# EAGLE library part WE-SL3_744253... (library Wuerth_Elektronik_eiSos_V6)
SMD Common Mode Line Filter WE-SL3 - Small size - Low Profile, only 2.5 mm - High Impedance tp to 5000 ohm - High Current up to 700mA - Low leakage inductance - USB - CAN - Firewire - Data Lines - Power Lines

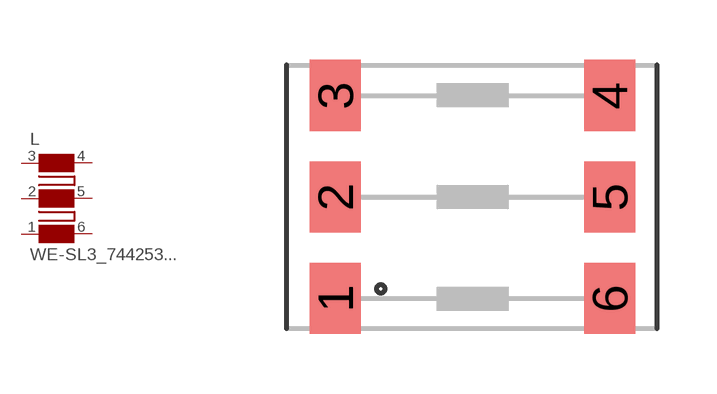
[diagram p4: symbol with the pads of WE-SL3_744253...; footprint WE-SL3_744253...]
Designator prefix L

## WE-SL3_744253...  [WE-SL3_744253...]
1  3  pas
2  2  pas
3  1  pas
4  6  pas
5  5  pas
6  4  pas

## Footprint WE-SL3_744253... (pad centres in mm)
SMD Common-Mode Line Filter WE-SL3
smd 1.27 x 1.78: 1 -3.44,-2.54; 2 -3.44,0; 3 -3.44,2.54; 4 3.42,2.54; 5 3.42,0; 6 3.42,-2.54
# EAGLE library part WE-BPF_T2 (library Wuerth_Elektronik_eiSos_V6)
SMD-Multilayer Chip Band-Pass Filter WE-BPF - low insertion loss - High attenuation - Guaranteed filter characteristics over a wide temperature range -- Rf applications in the frequency range up to 6GHz -- Wireless communcation systems like DECT, PACS, PHS, GSM,WLAN,Bluetooth,..

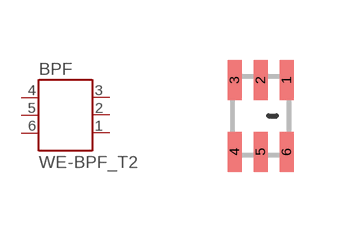
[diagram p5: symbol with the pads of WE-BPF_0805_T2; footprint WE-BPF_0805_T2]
Designator prefix BPF

## WE-BPF_T2_0805  [WE-BPF_0805_T2]
1  GND  pas
2  GND  pas
3  I/O  pas
4  GND  pas
5  GND  pas
6  I/O  pas

## Footprint WE-BPF_0805_T2 (pad centres in mm)
Multilayer Chip Band -Pass Filter WE-BPF
smd 0.35 x 1: 1 0.65,0.9; 2 0,0.9; 3 -0.65,0.9; 4 -0.65,-0.9; 5 0,-0.9; 6 0.65,-0.9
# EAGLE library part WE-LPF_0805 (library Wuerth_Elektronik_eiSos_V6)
Multilayer Chip Low-Pass Filters WE-LPF SMD 0603 - One inductor and three capacitors or two inductors and five capacitors in one component - Power capacity up to 3W - Low insertion loss and high attenuation in the stop-band -- RF-applications in the area of 0.8 to 6 GHz -- wireless communication systems like DECT,PACS,PHS,GSM, Bluetooth,...

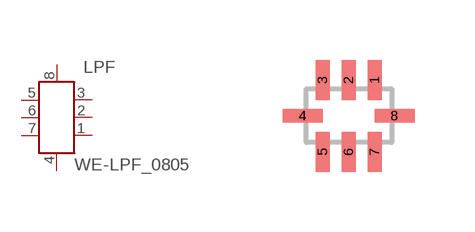
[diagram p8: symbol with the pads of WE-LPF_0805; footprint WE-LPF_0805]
Designator prefix LPF

## WE-LPF_0805  [WE-LPF_0805]
1  GND  pwr
2  NC  nc
3  GND  pwr
4  OUT  out
5  GND  pwr
6  NC  nc
7  GND  pwr
8  IN  in

## Footprint WE-LPF_0805 (pad centres in mm)
Multilayer Chip Low-Pass Filters WE-LPF
smd 0.35 x 1: 1 0.65,0.9; 2 0,0.9; 3 -0.65,0.9; 5 -0.65,-0.9; 6 0,-0.9; 7 0.65,-0.9
smd 1 x 0.35: 4 -1.15,0; 8 1.15,0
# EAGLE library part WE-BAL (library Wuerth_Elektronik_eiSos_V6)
Multilayer Chip Baluns WE-BAL - Low loss SMD Balun with balanced impedance of 50 to 200 Ohm - Operating temperature: -40°C to +85°C - Power Capacity: 3 W max. -- RF-applications in the area of 0.8 to 6 GHz -- Download S-Parameter on www.we-online.com -- Wireless communication systems like DECT, PACS, PHS, GSM, WLAN, Bluetooth

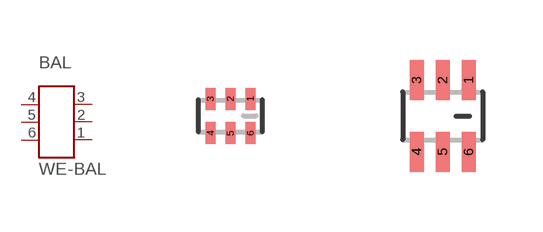
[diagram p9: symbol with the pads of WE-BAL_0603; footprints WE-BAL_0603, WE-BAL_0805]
Designator prefix BAL

## WE-BAL_0603  [WE-BAL_0603]
1  1  pas
2  2  pas
3  3  pas
4  4  pas
5  5  pas
6  6  pas

## WE-BAL_0805  [WE-BAL_0805]
Pads as for WE-BAL_0603

## WE-BAL_1206  [WE-BAL_1206]
Pads as for WE-BAL_0603

## Footprint WE-BAL_0603 (pad centres in mm)
Multilayer Chip Baluns WE-BAL
smd 0.25 x 0.55: 1 0.5,0.43; 2 0,0.43; 3 -0.5,0.43; 4 -0.5,-0.43; 5 0,-0.43; 6 0.5,-0.43

## Footprint WE-BAL_0805 (pad centres in mm)
Multilayer Chip Baluns WE-BAL
smd 0.35 x 1: 1 0.65,0.9; 2 0,0.9; 3 -0.65,0.9; 4 -0.65,-0.9; 5 0,-0.9; 6 0.65,-0.9

## Footprint WE-BAL_1206 (pad centres in mm)
Multilayer Chip Baluns WE-BAL
smd 0.65 x 1.1: 1 1,1; 2 0,1; 3 -1,1; 4 -1,-1; 5 0,-1; 6 1,-1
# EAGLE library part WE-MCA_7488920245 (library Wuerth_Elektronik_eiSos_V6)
Multilayer Chip Antenna WE-MCA - SMD Multilayer Chip Antenna - Extremely low profile - Very light component - Operating temperature: -40°C to +85°C - Power capacity: 3 W max. - Omni-directional -- For RF application in the area of 2,4 GHz -- WLAN -- Home RF (868 MHz) -- Bluetooth applications -- IEEE 802.11a/b -- GPS -- GSM -- WIMAX applications

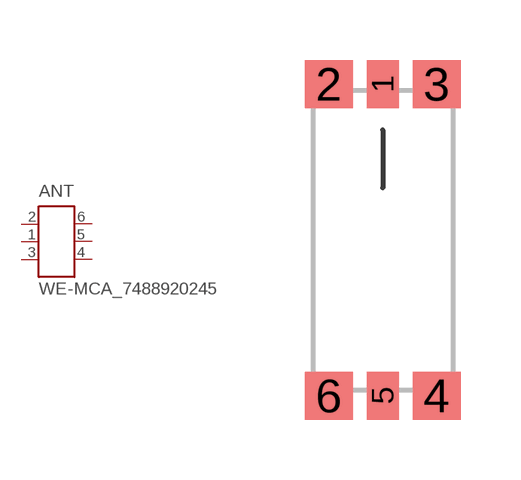
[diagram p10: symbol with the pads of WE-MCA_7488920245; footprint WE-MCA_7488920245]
Designator prefix ANT

## WE-MCA_7488920245  [WE-MCA_7488920245]
1  FD  pas
2  GND  pwr
3  GND  pwr
4  NC  nc
5  NC  nc
6  NC  nc

## Footprint WE-MCA_7488920245 (pad centres in mm)
Multiplayer Chip Antenna WE-MCA
smd 0.8 x 1.2: 1 0,3.9; 5 0,-3.9
smd 1.2 x 1.2: 2 -1.35,3.9; 3 1.35,3.9; 4 1.35,-3.9; 6 -1.35,-3.9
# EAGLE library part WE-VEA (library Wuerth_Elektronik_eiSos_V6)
WESURGE ESD Suppressor-Array WE-VEA - Fast response time (1 ns) - Low signal insertion loss - No leakage current - Low clamping voltage - Almost no energy consumption in stand-by mode - Excellent absorption for ESD-impulses -- Protection data lines -- Protection of bus systems -- Protection of video transmission lines -- Protection of semiconductors -- ESD protection in accordance with EN 61000-4-2

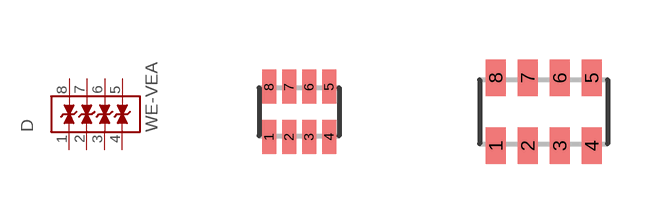
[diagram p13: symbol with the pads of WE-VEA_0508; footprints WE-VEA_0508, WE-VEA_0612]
Designator prefix D

## WE-VEA_0508  [WE-VEA_0508]
1  1  pas
2  2  pas
3  3  pas
4  4  pas
5  5  pas
6  6  pas
7  7  pas
8  8  pas

## WE-VEA_0612  [WE-VEA_0612]
Pads as for WE-VEA_0508

## Footprint WE-VEA_0508 (pad centres in mm)
WESURGE ESD Suppressor-Array WE-VEA
smd 0.35 x 0.85: 1 -0.75,-0.625; 2 -0.25,-0.625; 3 0.25,-0.625; 4 0.75,-0.625; 5 0.75,0.625; 6 0.25,0.625; 7 -0.25,0.625; 8 -0.75,0.625

## Footprint WE-VEA_0612 (pad centres in mm)
WESURGE ESD Suppressor-Array WE-VEA
smd 0.5 x 0.9: 1 -1.2,-0.85; 2 -0.4,-0.85; 3 0.4,-0.85; 4 1.2,-0.85; 5 1.2,0.85; 6 0.4,0.85; 7 -0.4,0.85; 8 -1.2,0.85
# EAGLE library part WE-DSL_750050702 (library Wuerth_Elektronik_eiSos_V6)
SMD-ADSL Transformer WE-DSL - IEC60950 compatible -- for ADSL applications -- Matched to various manufacturers ADSL ICs

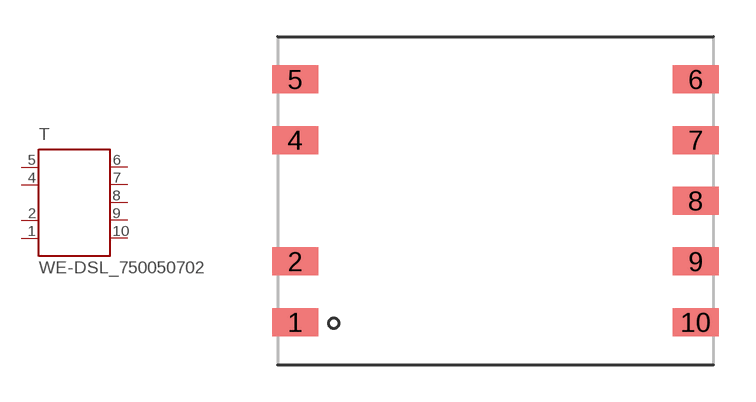
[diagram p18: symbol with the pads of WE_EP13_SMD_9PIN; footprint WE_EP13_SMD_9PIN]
Designator prefix T

## WE-DSL_750050702  [WE_EP13_SMD_9PIN]
1  1  pas
2  2  pas
4  4  pas
5  5  pas
6  6  pas
7  7  pas
8  8  pas
9  9  pas
10  10  pas

## Footprint WE_EP13_SMD_9PIN (pad centres in mm)
SMD-xDSL Transformer WE-DSL
smd 1.88 x 1.143: 1 -8.18,-4.96; 2 -8.18,-2.48; 4 -8.18,2.48; 5 -8.18,4.96; 6 8.18,4.96; 7 8.18,2.48; 8 8.18,0; 9 8.18,-2.48; 10 8.18,-4.96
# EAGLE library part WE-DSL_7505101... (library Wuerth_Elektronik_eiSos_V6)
SMD-VDSL Transformer WE-DSL - IEC60950 compatible -- for VDSL applications -- Matched to various manufacturers VDSL ICs

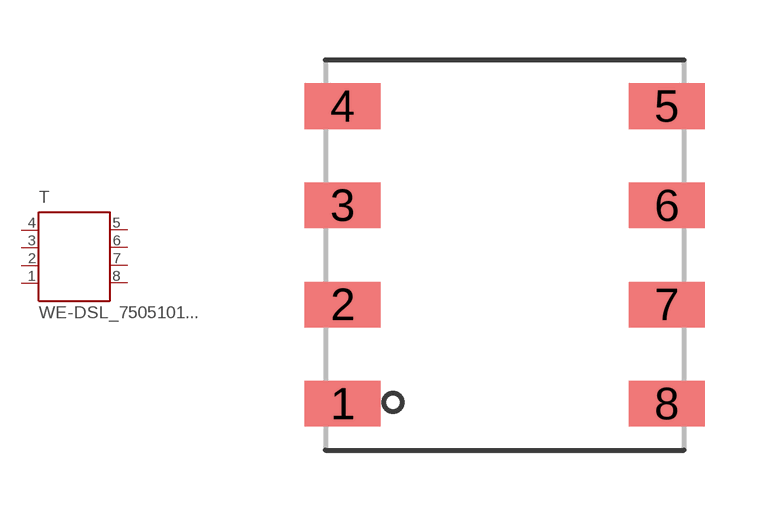
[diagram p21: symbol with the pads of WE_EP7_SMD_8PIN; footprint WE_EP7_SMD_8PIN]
Designator prefix T

## WE-DSL_7505101...  [WE_EP7_SMD_8PIN]
1  1  pas
2  2  pas
3  3  pas
4  4  pas
5  5  pas
6  6  pas
7  7  pas
8  8  pas

## Footprint WE_EP7_SMD_8PIN (pad centres in mm)
Transformer, EP7 SMD 8 Pin
smd 1.91 x 1.143: 1 -4.065,-3.735; 2 -4.065,-1.245; 3 -4.065,1.245; 4 -4.065,3.735; 5 4.065,3.735; 6 4.065,1.245; 7 4.065,-1.245; 8 4.065,-3.735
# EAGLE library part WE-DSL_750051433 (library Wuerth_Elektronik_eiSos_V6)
SMD-SHDSL Transformer WE-DSL - IEC60950 compatible -- for SHDSL applications -- Matched to various manufacturers SHDSL ICs

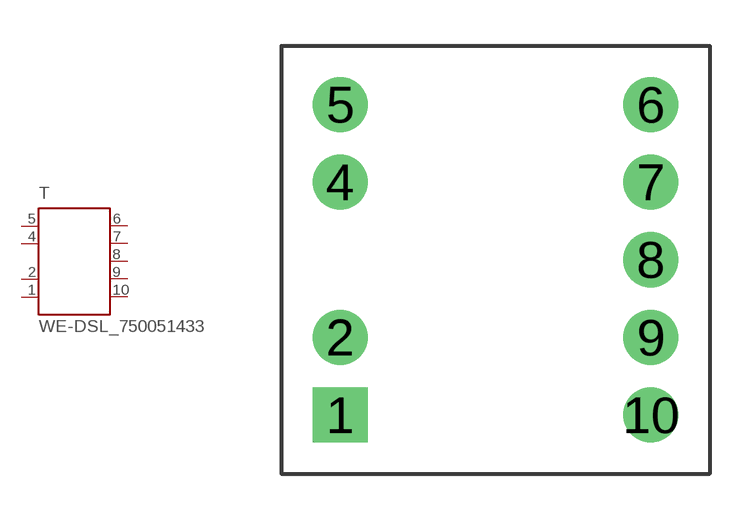
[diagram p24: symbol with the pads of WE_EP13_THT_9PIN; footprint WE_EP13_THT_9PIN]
Designator prefix T

## WE-DSL_750051433  [WE_EP13_THT_9PIN]
1  1  pas
2  2  pas
4  4  pas
5  5  pas
6  6  pas
7  7  pas
8  8  pas
9  9  pas
10  10  pas

## Footprint WE_EP13_THT_9PIN (pad centres in mm)
SMD-xDSL Transformer WE-DSL
drill 1.2 square: 1 -5.08,-5.08
drill 1.2: 2 -5.08,-2.54; 4 -5.08,2.54; 5 -5.08,5.08; 6 5.08,5.08; 7 5.08,2.54; 8 5.08,0; 9 5.08,-2.54; 10 5.08,-5.08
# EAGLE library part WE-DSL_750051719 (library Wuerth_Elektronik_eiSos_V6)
SMD-SHDSL Transformer WE-DSL - IEC60950 compatible -- for SHDSL applications -- Matched to various manufacturers SHDSL ICs

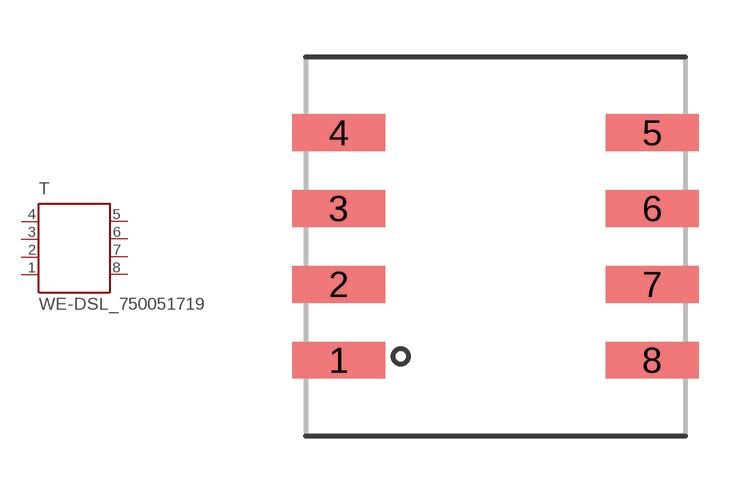
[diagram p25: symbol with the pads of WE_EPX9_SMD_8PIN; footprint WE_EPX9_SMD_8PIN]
Designator prefix T

## WE-DSL_750051719  [WE_EPX9_SMD_8PIN]
1  1  pas
2  2  pas
3  3  pas
4  4  pas
5  5  pas
6  6  pas
7  7  pas
8  8  pas

## Footprint WE_EPX9_SMD_8PIN (pad centres in mm)
Transformer, EPX9 SMD 8 Pin
smd 2.44 x 0.97: 1 -4.13,-3; 2 -4.13,-1; 3 -4.13,1; 4 -4.13,3; 5 4.13,3; 6 4.13,1; 7 4.13,-1; 8 4.13,-3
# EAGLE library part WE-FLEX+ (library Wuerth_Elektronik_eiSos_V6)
FLEX-Transformer WE-FLEX+ - Transformer with 6 windings - Power up to 300W - Insulation voltage 500 VDC - Low leakage inductance -- For all kinds of switching regulators: Flyback converters, Forward converters, Push- pull converters, SEPIC converter

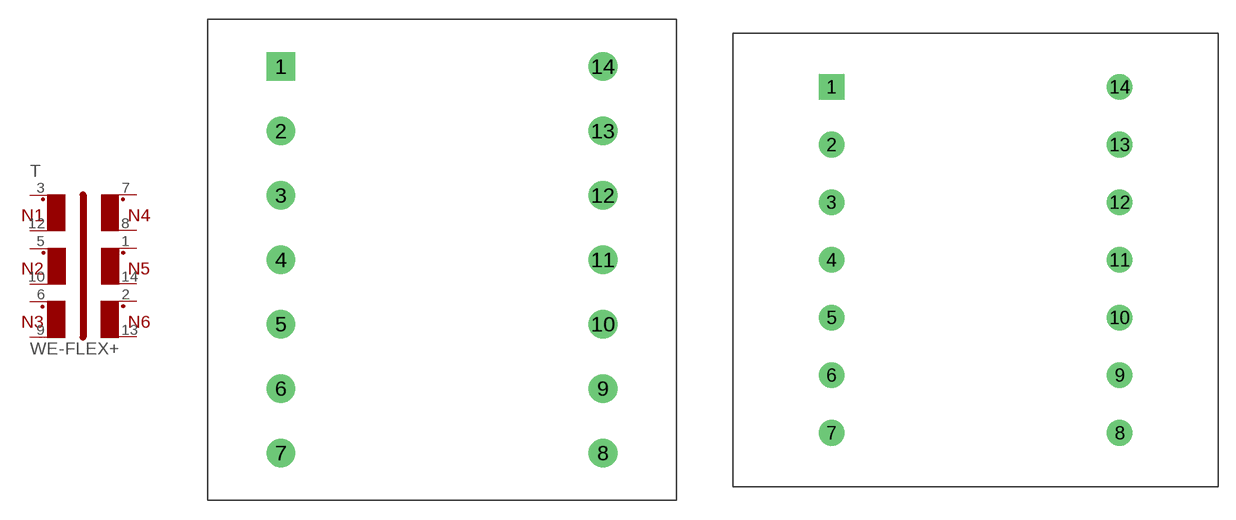
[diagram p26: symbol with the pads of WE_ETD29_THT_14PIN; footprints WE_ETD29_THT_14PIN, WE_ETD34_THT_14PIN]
Designator prefix T

## WE-FLEX+_ETD29  [WE_ETD29_THT_14PIN]
1  9  pas
2  11  pas
3  1  pas
5  3  pas
6  5  pas
7  7  pas
8  8  pas
9  6  pas
10  4  pas
12  2  pas
13  12  pas
14  10  pas

## WE-FLEX+_ETD34  [WE_ETD34_THT_14PIN]
Pads as for WE_ETD29_THT_14PIN

## WE-FLEX+_ETD39  [WE_ETD39_THT_16PIN]
2  9  pas
3  11  pas
4  1  pas
5  3  pas
6  5  pas
7  7  pas
10  8  pas
11  6  pas
12  4  pas
13  2  pas
14  12  pas
15  10  pas

## Footprint WE_ETD29_THT_14PIN (pad centres in mm)
Transformer, ETD29 THT 14Pin
drill 1.5 square: 1 -12.7,15.25
drill 1.5: 2 -12.7,10.16; 3 -12.7,5.08; 4 -12.7,0; 5 -12.7,-5.08; 6 -12.7,-10.16; 7 -12.7,-15.25; 8 12.7,-15.25; 9 12.7,-10.16; 10 12.7,-5.08; 11 12.7,0; 12 12.7,5.08; 13 12.7,10.16; 14 12.7,15.25

## Footprint WE_ETD34_THT_14PIN (pad centres in mm)
Transformer, ETD34 THT 14Pin
drill 1.5 square: 1 -12.7,15.25
drill 1.5: 2 -12.7,10.16; 3 -12.7,5.08; 4 -12.7,0; 5 -12.7,-5.08; 6 -12.7,-10.16; 7 -12.7,-15.25; 8 12.7,-15.25; 9 12.7,-10.16; 10 12.7,-5.08; 11 12.7,0; 12 12.7,5.08; 13 12.7,10.16; 14 12.7,15.25

## Footprint WE_ETD39_THT_16PIN (pad centres in mm)
Transformer, ETD39 THT 16Pin
drill 1.4 square: 1 -15.24,17.78
drill 1.4: 2 -15.24,12.7; 3 -15.24,7.62; 4 -15.24,2.54; 5 -15.24,-2.54; 6 -15.24,-7.62; 7 -15.24,-12.7; 8 -15.24,-17.78; 9 15.24,-17.78; 10 15.24,-12.7; 11 15.24,-7.62; 12 15.24,-2.54; 13 15.24,2.54; 14 15.24,7.62; 15 15.24,12.7; 16 15.24,17.78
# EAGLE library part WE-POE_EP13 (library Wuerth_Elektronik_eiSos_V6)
Transformer for Power-over-Ethernet WE-PoE - Flyback converter transducer particularly for PoE PDs - Insulation voltage 1,5 kVAC/1 min - Input voltages 36V till 57V -- Flyback converters -- Power-over-Ethernet PDs

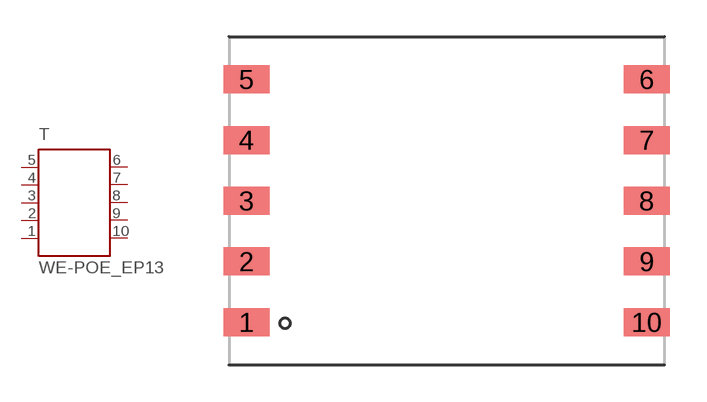
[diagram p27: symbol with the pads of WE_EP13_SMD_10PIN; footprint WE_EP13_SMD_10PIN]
Designator prefix T

## WE-POE_EP13  [WE_EP13_SMD_10PIN]
1  5  pas
2  4  pas
3  3  pas
4  2  pas
5  1  pas
6  10  pas
7  9  pas
8  8  pas
9  7  pas
10  6  pas

## Footprint WE_EP13_SMD_10PIN (pad centres in mm)
Transformer, EP13 SMD 10 Pin
smd 1.88 x 1.143: 1 -8.18,-4.96; 2 -8.18,-2.48; 3 -8.18,0; 4 -8.18,2.48; 5 -8.18,4.96; 6 8.18,4.96; 7 8.18,2.48; 8 8.18,0; 9 8.18,-2.48; 10 8.18,-4.96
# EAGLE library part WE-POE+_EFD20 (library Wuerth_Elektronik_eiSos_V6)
Transformer for Power-over-Ethernet WE-PoE+ - Designed to meet 30W PoE+ objectives of IEEE802.3at - Frequency range: 250-400 kHz - Insulation voltage 1,5 kVAC/1 min - Input voltages 36V till 72V -- PoE+ Powered devices -- Ip phones -- WLAN-Access point -- Security cameras

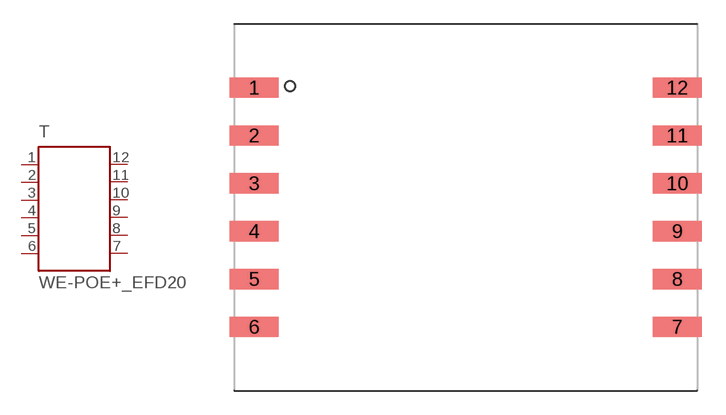
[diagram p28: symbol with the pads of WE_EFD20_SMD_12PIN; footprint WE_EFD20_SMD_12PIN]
Designator prefix T

## WE-POE+_EFD20  [WE_EFD20_SMD_12PIN]
1  1  pas
2  2  pas
3  3  pas
4  4  pas
5  5  pas
6  6  pas
7  7  pas
8  8  pas
9  9  pas
10  10  pas
11  11  pas
12  12  pas

## Footprint WE_EFD20_SMD_12PIN (pad centres in mm)
Transformer, EFD20 SMD 12 Pin
smd 3.05 x 1.27: 1 -13.26,7.5; 2 -13.26,4.5; 3 -13.26,1.5; 4 -13.26,-1.5; 5 -13.26,-4.5; 6 -13.26,-7.5; 7 13.26,-7.5; 8 13.26,-4.5; 9 13.26,-1.5; 10 13.26,1.5; 11 13.26,4.5; 12 13.26,7.5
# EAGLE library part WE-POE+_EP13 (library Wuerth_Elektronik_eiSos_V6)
Transformer for Power-over-Ethernet WE-PoE+ - Designed to meet 30W PoE+ objectives of IEEE802.3at - Frequency range: 250-400 kHz - Insulation voltage 1,5 kVAC/1 min - Input voltages 36V till 72V -- PoE+ Powered devices -- Ip phones -- WLAN-Access point -- Security cameras

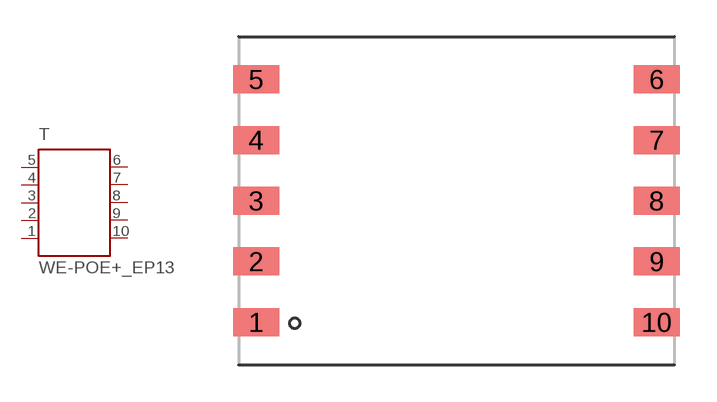
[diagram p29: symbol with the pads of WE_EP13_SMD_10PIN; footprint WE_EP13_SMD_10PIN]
Designator prefix T

## WE-POE+_EP13  [WE_EP13_SMD_10PIN]
1  5  pas
2  4  pas
3  3  pas
4  2  pas
5  1  pas
6  10  pas
7  9  pas
8  8  pas
9  7  pas
10  6  pas

## Footprint WE_EP13_SMD_10PIN (pad centres in mm)
Transformer, EP13 SMD 10 Pin
smd 1.88 x 1.143: 1 -8.18,-4.96; 2 -8.18,-2.48; 3 -8.18,0; 4 -8.18,2.48; 5 -8.18,4.96; 6 8.18,4.96; 7 8.18,2.48; 8 8.18,0; 9 8.18,-2.48; 10 8.18,-4.96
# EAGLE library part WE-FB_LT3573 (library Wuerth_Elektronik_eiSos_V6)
Flyback Converter WE-FB for LT3573 - Input voltage: 24 V - Output power: 5 W - Isolation voltage: 1.5 kV - designd for LT3573 -- Industrial input voltage

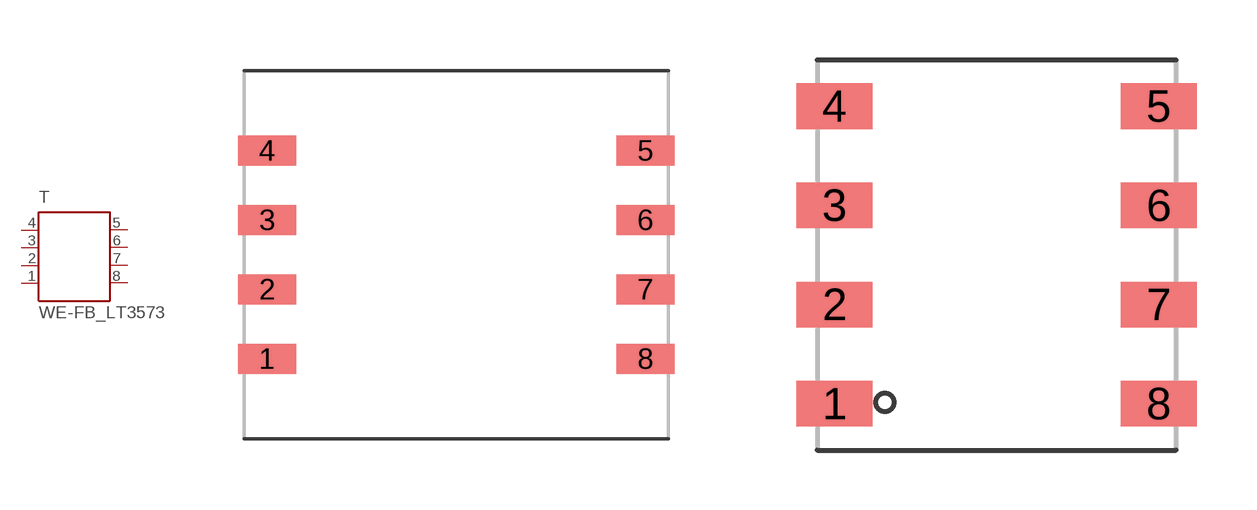
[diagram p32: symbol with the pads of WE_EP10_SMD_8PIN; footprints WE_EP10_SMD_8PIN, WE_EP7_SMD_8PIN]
Designator prefix T

## WE-FB_LT3573_WE-FB_EP10  [WE_EP10_SMD_8PIN]
1  1  pas
2  2  pas
3  3  pas
4  4  pas
5  5  pas
6  6  pas
7  7  pas
8  8  pas

## WE-FB_LT3573_WE-FB_EP7  [WE_EP7_SMD_8PIN]
Pads as for WE_EP10_SMD_8PIN

## WE-FB_LT3573_WE-FB_750370047  [WE_EP7*_750370047]
Pads as for WE_EP10_SMD_8PIN

## WE-FB_LT3573_WE-FB_750370058_750370059  [WE_EP7*_750370058_750370059]
Pads as for WE_EP10_SMD_8PIN

## WE-FB_LT3573_WE-FB_ER9.5  [WE_ER9.5_SMD_8PIN]
1  4  pas
2  3  pas
3  2  pas
4  1  pas
5  8  pas
6  7  pas
7  6  pas
8  5  pas

## Footprint WE_EP10_SMD_8PIN (pad centres in mm)
Transformer, EP10 SMD 8 Pin
smd 2.08 x 1.07: 1 -6.78,-3.735; 2 -6.78,-1.245; 3 -6.78,1.245; 4 -6.78,3.735; 5 6.78,3.735; 6 6.78,1.245; 7 6.78,-1.245; 8 6.78,-3.735

## Footprint WE_EP7_SMD_8PIN (pad centres in mm)
Transformer, EP7 SMD 8 Pin
smd 1.91 x 1.143: 1 -4.065,-3.735; 2 -4.065,-1.245; 3 -4.065,1.245; 4 -4.065,3.735; 5 4.065,3.735; 6 4.065,1.245; 7 4.065,-1.245; 8 4.065,-3.735

## Footprint WE_EP7*_750370047 (pad centres in mm)
Transformer, EP7* SMD 8Pin für WE-FB
smd 1.96 x 1.17: 1 -6.16,-3.735; 2 -6.16,-1.245; 3 -6.16,1.245; 4 -6.16,3.735; 5 6.16,3.735; 6 6.16,1.245; 7 6.16,-1.245; 8 6.16,-3.735

## Footprint WE_EP7*_750370058_750370059 (pad centres in mm)
Transformer, EP7* SMD 8Pin für WE-FB
smd 1.96 x 1.17: 1 -5.83,-3.75; 2 -5.83,-1.25; 3 -5.83,1.25; 4 -5.83,3.75; 5 5.83,3.75; 6 5.83,1.25; 7 5.83,-1.25; 8 5.83,-3.75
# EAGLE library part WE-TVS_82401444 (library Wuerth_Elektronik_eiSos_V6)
TVS Diode Array WE-TVS, Super Speed Serie - Low capazity - No leakage current - Low clamping voltage - high ESD voltage protection -- SATA -- DisplayPort -- DVI -- HDMI

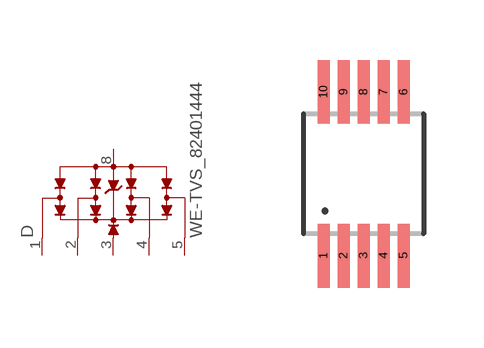
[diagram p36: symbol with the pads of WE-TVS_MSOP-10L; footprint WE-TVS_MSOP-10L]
Designator prefix D

## WE-TVS_82401444  [WE-TVS_MSOP-10L]
1  1  pas
2  2  pas
3  VDD  pwr
4  3  pas
5  4  pas
8  GND  pwr

## Footprint WE-TVS_MSOP-10L (pad centres in mm)
TVS Diode Array WE-TVS
smd 0.3 x 1.6: 1 -1,-2.05; 2 -0.5,-2.05; 3 0,-2.05; 4 0.5,-2.05; 5 1,-2.05; 6 1,2.05; 7 0.5,2.05; 8 0,2.05; 9 -0.5,2.05; 10 -1,2.05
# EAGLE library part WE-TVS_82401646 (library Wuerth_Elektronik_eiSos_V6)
TVS Diode Array WE-TVS, Super Speed Serie - Low capazity - No leakage current - Low clamping voltage - high ESD voltage protection -- USB 3.0

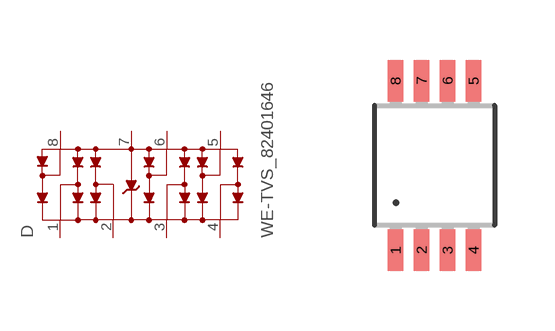
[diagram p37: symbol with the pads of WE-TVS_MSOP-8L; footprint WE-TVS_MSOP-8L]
Designator prefix D

## WE-TVS_82401646  [WE-TVS_MSOP-8L]
1  1  pas
2  2  pas
3  3  pas
4  4  pas
5  5  pas
6  6  pas
7  GND  pwr
8  VDD  pwr

## Footprint WE-TVS_MSOP-8L (pad centres in mm)
TVS Diode Array WE-TVS
smd 0.38 x 1.04: 1 -0.975,-2.12; 2 -0.325,-2.12; 3 0.325,-2.12; 4 0.975,-2.12; 5 0.975,2.12; 6 0.325,2.12; 7 -0.325,2.12; 8 -0.975,2.12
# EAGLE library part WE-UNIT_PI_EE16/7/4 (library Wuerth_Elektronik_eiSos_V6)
Off-Line Transformer WE-Unit PI - Nominal input voltage: 85-265 VAC - Output power 4.2 W - Operating temperature: -40°C to +125 °C - Clearance and creepage distance 6 mm min. - Isolation voltage 4 kVAC -- Especially designed for several ICs from Power Integrations LNK605 -- Universal input -- Offline-switch mode power supplies

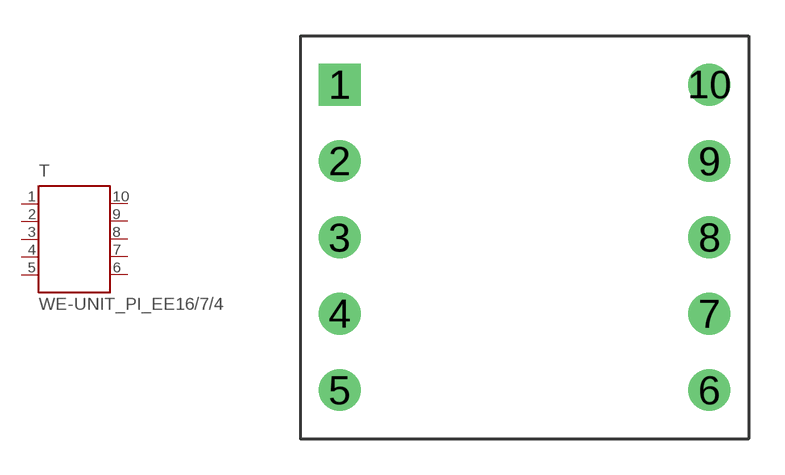
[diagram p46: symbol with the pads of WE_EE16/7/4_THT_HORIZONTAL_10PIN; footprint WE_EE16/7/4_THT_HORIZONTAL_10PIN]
Designator prefix T

## WE-UNIT_PI_EE16/7/4  [WE_EE16/7/4_THT_HORIZONTAL_10PIN]
1  1  pas
2  2  pas
3  3  pas
4  4  pas
5  5  pas
6  6  pas
7  7  pas
8  8  pas
9  9  pas
10  10  pas

## Footprint WE_EE16/7/4_THT_HORIZONTAL_10PIN (pad centres in mm)
Transformer, EE16/7/4 THT Horizontal 10 Pin
drill 1.17 square: 1 -7.75,6.4
drill 1.17: 2 -7.75,3.2; 3 -7.75,0; 4 -7.75,-3.2; 5 -7.75,-6.4; 6 7.75,-6.4; 7 7.75,-3.2; 8 7.75,0; 9 7.75,3.2; 10 7.75,6.4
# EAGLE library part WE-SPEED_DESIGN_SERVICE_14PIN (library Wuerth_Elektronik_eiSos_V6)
WE-Speedy Design Service, 14 Pin - Any application that fits package style - Switch Mode Power: Flyback, Forward, Push-Pull, Coupled Inductor -- Telecom Applications: xDSL, POTS Splitter Inductors

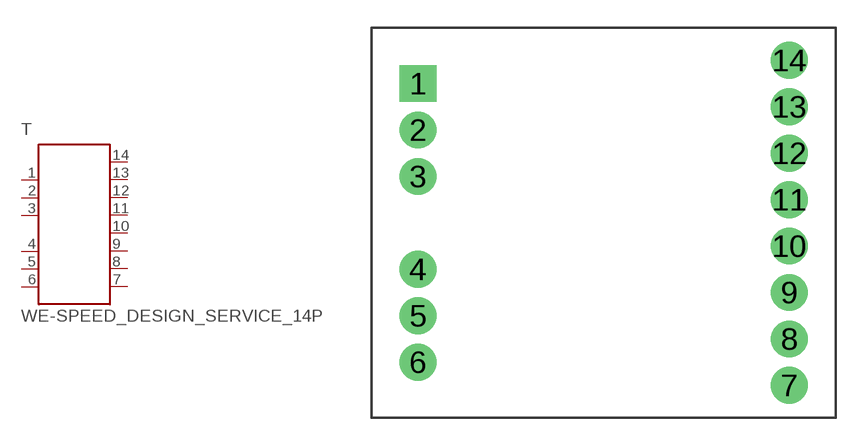
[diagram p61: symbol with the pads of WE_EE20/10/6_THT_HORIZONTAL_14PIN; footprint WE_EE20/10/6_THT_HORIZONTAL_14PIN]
Designator prefix T

## WE-SPEED_DESIGN_SERVICE_14PIN_EE20/10/6_THT  [WE_EE20/10/6_THT_HORIZONTAL_14PIN]
1  1  pas
2  2  pas
3  3  pas
4  4  pas
5  5  pas
6  6  pas
7  7  pas
8  8  pas
9  9  pas
10  10  pas
11  11  pas
12  12  pas
13  13  pas
14  14  pas

## Footprint WE_EE20/10/6_THT_HORIZONTAL_14PIN (pad centres in mm)
Transformer, EE20/10/6 THT Horizontal 14 Pin
drill 1.32 square: 1 -10,7.5
drill 1.32: 2 -10,5; 3 -10,2.5; 4 -10,-2.5; 5 -10,-5; 6 -10,-7.5; 7 10,-8.75; 8 10,-6.25; 9 10,-3.75; 10 10,-1.25; 11 10,1.25; 12 10,3.75; 13 10,6.25; 14 10,8.75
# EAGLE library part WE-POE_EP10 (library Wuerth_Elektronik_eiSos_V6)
Transformer for Power-over-Ethernet WE-PoE - Flyback converter transducer particularly for PoE PDs - Insulation voltage 1,5 kVAC/1 min - Input voltages 36V till 80V -- Flyback converters -- Power-over-Ethernet PDs

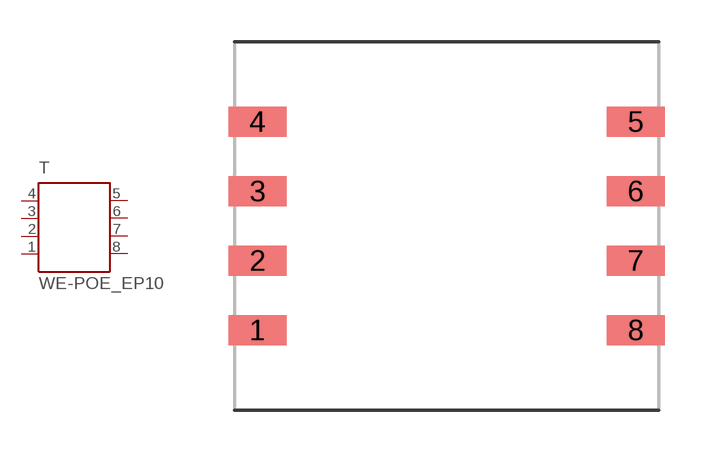
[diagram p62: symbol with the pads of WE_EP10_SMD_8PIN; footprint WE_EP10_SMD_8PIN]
Designator prefix T

## WE-POE_EP10  [WE_EP10_SMD_8PIN]
1  1  pas
2  2  pas
3  3  pas
4  4  pas
5  5  pas
6  6  pas
7  7  pas
8  8  pas

## Footprint WE_EP10_SMD_8PIN (pad centres in mm)
Transformer, EP10 SMD 8 Pin
smd 2.08 x 1.07: 1 -6.78,-3.735; 2 -6.78,-1.245; 3 -6.78,1.245; 4 -6.78,3.735; 5 6.78,3.735; 6 6.78,1.245; 7 6.78,-1.245; 8 6.78,-3.735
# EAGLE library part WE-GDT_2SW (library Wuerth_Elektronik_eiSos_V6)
SMD Gate Drive Transformer WE-GDT - small form factor EP5 - 1 or 2 secondary windings - 4 different turn rations - 1500VDC insulation test voltage - operating voltage up to 80V -- Gate Drive -- Signal -- Power -- Synchronous Flyback

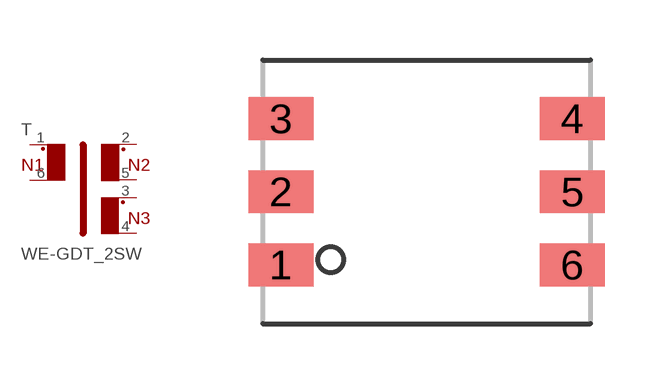
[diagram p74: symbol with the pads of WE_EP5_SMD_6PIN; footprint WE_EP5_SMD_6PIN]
Designator prefix T

## WE-GDT_2SW_760301103  [WE_EP5_SMD_6PIN]
1  1  pas
2  3  pas
3  5  pas
4  6  pas
5  4  pas
6  2  pas

## WE-GDT_2SW_760301104  [WE_EP5_SMD_6PIN]
Pads as for WE_EP5_SMD_6PIN

## WE-GDT_2SW_760301105  [WE_EP5_SMD_6PIN]
Pads as for WE_EP5_SMD_6PIN

## Footprint WE_EP5_SMD_6PIN (pad centres in mm)
Transformer, EP5 SMD 6 Pin
smd 1.63 x 1.07: 1 -3.645,-1.83; 2 -3.645,0; 3 -3.645,1.83; 4 3.645,1.83; 5 3.645,0; 6 3.645,-1.83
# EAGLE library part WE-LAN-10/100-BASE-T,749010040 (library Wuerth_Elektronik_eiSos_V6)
LAN-Transformer WE-LAN 10/100 Base T - Compliant with IEEE 802.3 standards - SMD -- Ethernet -- Power over Ethernet -- 1 Gigabit Ethernet -- Compliant with most IC's for ethernet applications like Intel, AMD, Globespan and Realtek -- Hub, Router, Switch

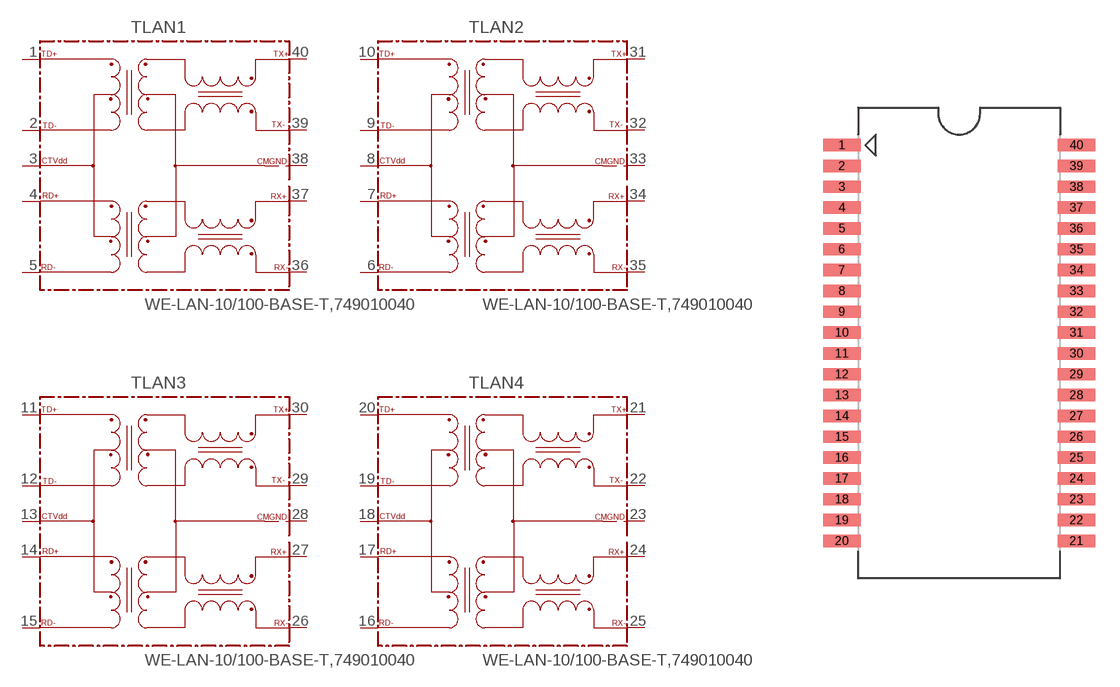
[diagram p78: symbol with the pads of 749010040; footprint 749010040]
Designator prefix T; gates LAN1=749010040 LAN2=749010040 LAN3=749010040 LAN4=749010040

## WE-LAN-10/100-BASE-T,749010040 (COMPANY-URL: http://www.we-online.de; CREATED-BY: Christin Zierenner; CREATED-DATE: June 2012; DATASHEET-URL: http://katalog.we-online.de/kataloge/eisos/media/pdf/749010040.pdf; MANUFACTURER: Würth Elektronik eiSos GmbH)  [749010040]
1  LAN1:TD+
2  LAN1:TD-
3  LAN1:CTVDD
4  LAN1:RD+
5  LAN1:RD-
6  LAN2:RD-
7  LAN2:RD+
8  LAN2:CTVDD
9  LAN2:TD-
10  LAN2:TD+
11  LAN3:TD+
12  LAN3:TD-
13  LAN3:CTVDD
14  LAN3:RD+
15  LAN3:RD-
16  LAN4:RD-
17  LAN4:RD+
18  LAN4:CTVDD
19  LAN4:TD-
20  LAN4:TD+
21  LAN4:TX+
22  LAN4:TX-
23  LAN4:CMGND
24  LAN4:RX+
25  LAN4:RX-
26  LAN3:RX-
27  LAN3:RX+
28  LAN3:CMGND
29  LAN3:TX-
30  LAN3:TX+
31  LAN2:TX+
32  LAN2:TX-
33  LAN2:CMGND
34  LAN2:RX+
35  LAN2:RX-
36  LAN1:RX-
37  LAN1:RX+
38  LAN1:CMGND
39  LAN1:TX-
40  LAN1:TX+

## Footprint 749010040 (pad centres in mm)
MAX Height =5.97mm
smd 2.29 x 0.76: 1 -7.15,12.065; 2 -7.15,10.795; 3 -7.15,9.525; 4 -7.15,8.255; 5 -7.15,6.985; 6 -7.15,5.715; 7 -7.15,4.445; 8 -7.15,3.175; 9 -7.15,1.905; 10 -7.15,0.635; 11 -7.15,-0.635; 12 -7.15,-1.905; 13 -7.15,-3.175; 14 -7.15,-4.445; 15 -7.15,-5.715; 16 -7.15,-6.985; 17 -7.15,-8.255; 18 -7.15,-9.525; 19 -7.15,-10.795; 20 -7.15,-12.065; 21 7.15,-12.065; 22 7.15,-10.795; 23 7.15,-9.525; 24 7.15,-8.255; 25 7.15,-6.985; 26 7.15,-5.715; 27 7.15,-4.445; 28 7.15,-3.175; 29 7.15,-1.905; 30 7.15,-0.635; 31 7.15,0.635; 32 7.15,1.905; 33 7.15,3.175; 34 7.15,4.445; 35 7.15,5.715; 36 7.15,6.985; 37 7.15,8.255; 38 7.15,9.525; 39 7.15,10.795; 40 7.15,12.065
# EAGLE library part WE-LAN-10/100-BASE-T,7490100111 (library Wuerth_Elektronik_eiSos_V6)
LAN-Transformer WE-LAN 10/100 Base T - Compliant with IEEE 802.3 standards - SMD -- Ethernet -- Power over Ethernet -- 1 Gigabit Ethernet -- Compliant with most IC's for ethernet applications like Intel, AMD, Globespan and Realtek -- Hub, Router, Switch

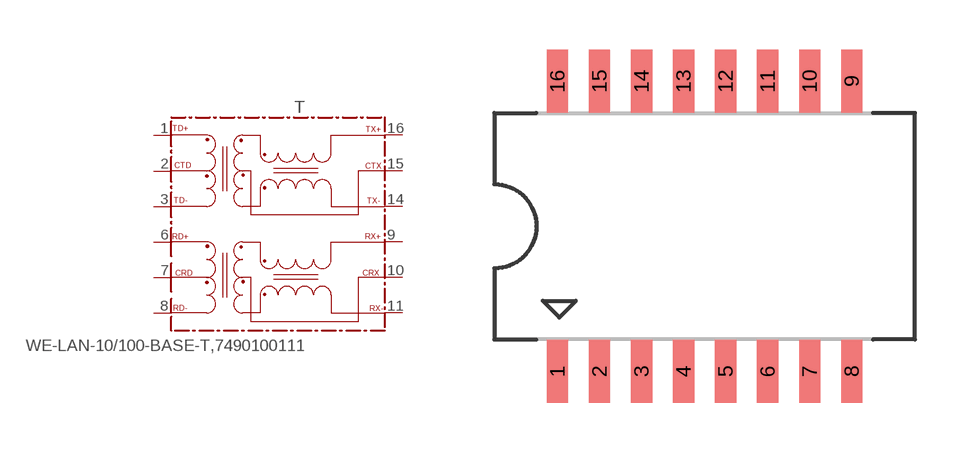
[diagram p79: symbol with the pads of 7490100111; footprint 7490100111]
Designator prefix T

## WE-LAN-10/100-BASE-T,7490100111 (COMPANY-URL: http://www.we-online.de; CREATED-BY: Christin Zierenner; CREATED-DATE: June 2012; DATASHEET-URL: http://katalog.we-online.de/kataloge/eisos/media/pdf/7490100111.pdf; MANUFACTURER: Würth Elektronik eiSos GmbH)  [7490100111]
1  TD+
2  CTD
3  TD-
6  RD+
7  CRD
8  RD-
9  RX+
10  CRX
11  RX-
14  TX-
15  CTX
16  TX+

## Footprint 7490100111 (pad centres in mm)
MAX Height=5.08mm
smd 0.64 x 1.91: 1 -4.445,-4.385; 2 -3.175,-4.385; 3 -1.905,-4.385; 4 -0.635,-4.385; 5 0.635,-4.385; 6 1.905,-4.385; 7 3.175,-4.385; 8 4.445,-4.385; 9 4.445,4.385; 10 3.175,4.385; 11 1.905,4.385; 12 0.635,4.385; 13 -0.635,4.385; 14 -1.905,4.385; 15 -3.175,4.385; 16 -4.445,4.385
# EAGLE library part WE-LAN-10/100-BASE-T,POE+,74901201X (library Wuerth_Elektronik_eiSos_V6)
LAN-Transformer WE-LAN 10/100 Base Tx - Compliant with IEEE 802.3 standards - SMD -- Ethernet -- Power over Ethernet -- 1 Gigabit Ethernet -- Compliant with most IC's for ethernet applications like Intel, AMD, Globespan and Realtek -- Hub, Router, Switch

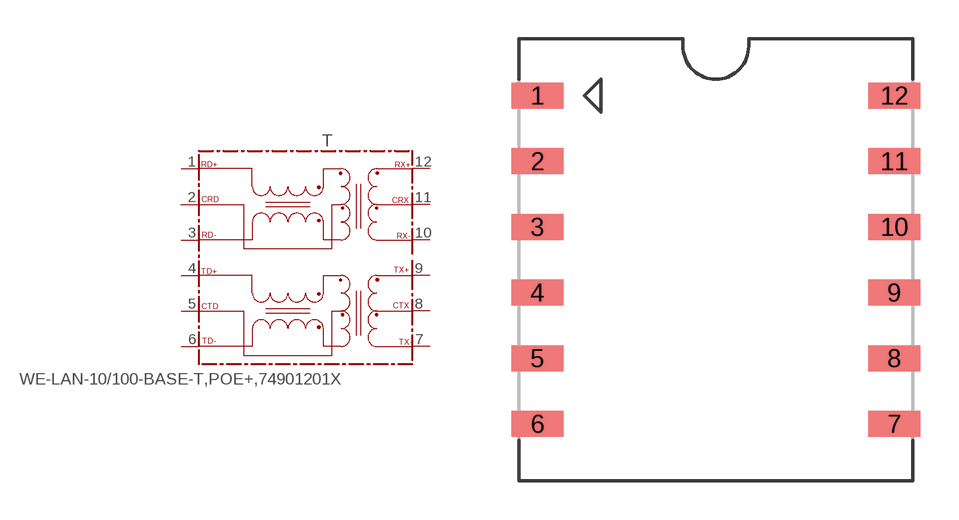
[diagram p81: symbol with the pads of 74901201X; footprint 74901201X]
Designator prefix T

## WE-LAN-10/100-BASE-T,POE+,74901201X(749012011) (COMPANY-URL: http://www.we-online.de; CREATED-BY: Christin Zierenner; CREATED-DATE: June 2012; DATASHEET-URL: http://katalog.we-online.de/kataloge/eisos/media/pdf/749012011.pdf; MANUFACTURER: Würth Elektronik eiSos GmbH)  [74901201X]
1  RD+
2  CRD
3  RD-
4  TD+
5  CTD
6  TD-
7  TX-
8  CTX
9  TX+
10  RX-
11  CRX
12  RX+

## WE-LAN-10/100-BASE-T,POE+,74901201X(749012013) (COMPANY-URL: http://www.we-online.de; CREATED-BY: Christin Zierenner; CREATED-DATE: June 2012; DATASHEET-URL: http://katalog.we-online.de/kataloge/eisos/media/pdf/749012013.pdf; MANUFACTURER: Würth Elektronik eiSos GmbH)  [74901201X]
Pads as for 74901201X

## Footprint 74901201X (pad centres in mm)
MAX Height = 8.4mm
smd 2 x 1: 1 -6.9,6.35; 2 -6.9,3.81; 3 -6.9,1.27; 4 -6.9,-1.27; 5 -6.9,-3.81; 6 -6.9,-6.35; 7 6.9,-6.35; 8 6.9,-3.81; 9 6.9,-1.27; 10 6.9,1.27; 11 6.9,3.81; 12 6.9,6.35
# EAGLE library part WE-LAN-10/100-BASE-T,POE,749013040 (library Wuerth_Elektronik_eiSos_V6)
LAN-Transformer WE-LAN 10/100 Base Tx - Compliant with IEEE 802.3 standards - SMD -- Ethernet -- Power over Ethernet -- 1 Gigabit Ethernet -- Compliant with most IC's for ethernet applications like Intel, AMD, Globespan and Realtek -- Hub, Router, Switch

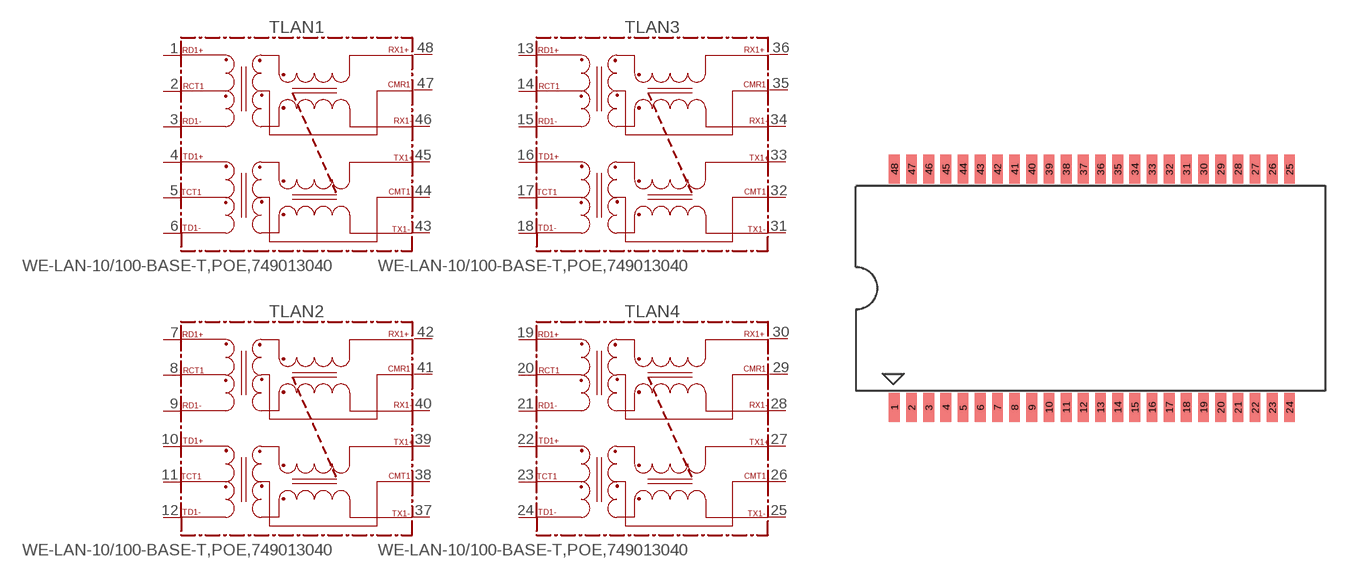
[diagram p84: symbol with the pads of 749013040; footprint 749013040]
Designator prefix T; gates LAN1=749013040 LAN2=749013040 LAN3=749013040 LAN4=749013040

## WE-LAN-10/100-BASE-T,POE,749013040 (COMPANY-URL: http://www.we-online.de; CREATED-BY: Christin Zierenner; CREATED-DATE: June 2012; DATASHEET-URL: http://katalog.we-online.de/kataloge/eisos/media/pdf/749013040.pdf; MANUFACTURER: Würth Elektronik eiSos GmbH)  [749013040]
1  LAN1:RD1+
2  LAN1:RCT1
3  LAN1:RD1-
4  LAN1:TD1+
5  LAN1:TCT1
6  LAN1:TD1-
7  LAN2:RD1+
8  LAN2:RCT1
9  LAN2:RD1-
10  LAN2:TD1+
11  LAN2:TCT1
12  LAN2:TD1-
13  LAN3:RD1+
14  LAN3:RCT1
15  LAN3:RD1-
16  LAN3:TD1+
17  LAN3:TCT1
18  LAN3:TD1-
19  LAN4:RD1+
20  LAN4:RCT1
21  LAN4:RD1-
22  LAN4:TD1+
23  LAN4:TCT1
24  LAN4:TD1-
25  LAN4:TX1-
26  LAN4:CMT1
27  LAN4:TX1+
28  LAN4:RX1-
29  LAN4:CMR1
30  LAN4:RX1+
31  LAN3:TX1-
32  LAN3:CMT1
33  LAN3:TX1+
34  LAN3:RX1-
35  LAN3:CMR1
36  LAN3:RX1+
37  LAN2:TX1-
38  LAN2:CMT1
39  LAN2:TX1+
40  LAN2:RX1-
41  LAN2:CMR1
42  LAN2:RX1+
43  LAN1:TX1-
44  LAN1:CMT1
45  LAN1:TX1+
46  LAN1:RX1-
47  LAN1:CMR1
48  LAN1:RX1+

## Footprint 749013040 (pad centres in mm)
MAX Height =7.24mm
smd 0.64 x 1.72: 1 -11.68,-7.08; 2 -10.66,-7.08; 3 -9.64,-7.08; 4 -8.62,-7.08; 5 -7.6,-7.08; 6 -6.58,-7.08; 7 -5.56,-7.08; 8 -4.54,-7.08; 9 -3.52,-7.08; 10 -2.5,-7.08; 11 -1.48,-7.08; 12 -0.46,-7.08; 13 0.56,-7.08; 14 1.58,-7.08; 15 2.6,-7.08; 16 3.62,-7.08; 17 4.64,-7.08; 18 5.66,-7.08; 19 6.68,-7.08; 20 7.7,-7.08; 21 8.72,-7.08; 22 9.74,-7.08; 23 10.76,-7.08; 24 11.78,-7.08; 25 11.78,7.08; 26 10.76,7.08; 27 9.74,7.08; 28 8.72,7.08; 29 7.7,7.08; 30 6.68,7.08; 31 5.66,7.08; 32 4.64,7.08; 33 3.62,7.08; 34 2.6,7.08; 35 1.58,7.08; 36 0.56,7.08; 37 -0.46,7.08; 38 -1.48,7.08; 39 -2.5,7.08; 40 -3.52,7.08; 41 -4.54,7.08; 42 -5.56,7.08; 43 -6.58,7.08; 44 -7.6,7.08; 45 -8.62,7.08; 46 -9.64,7.08; 47 -10.66,7.08; 48 -11.68,7.08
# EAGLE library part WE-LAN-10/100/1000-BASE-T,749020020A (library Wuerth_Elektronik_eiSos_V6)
LAN-Transformer WE-LAN 10/100/1000 Base Tx - Compliant with IEEE 802.3 standards - SMD -- Ethernet -- Power over Ethernet -- 1 Gigabit Ethernet -- Compliant with most IC's for ethernet applications like Intel, AMD, Globespan and Realtek -- Hub, Router, Switch

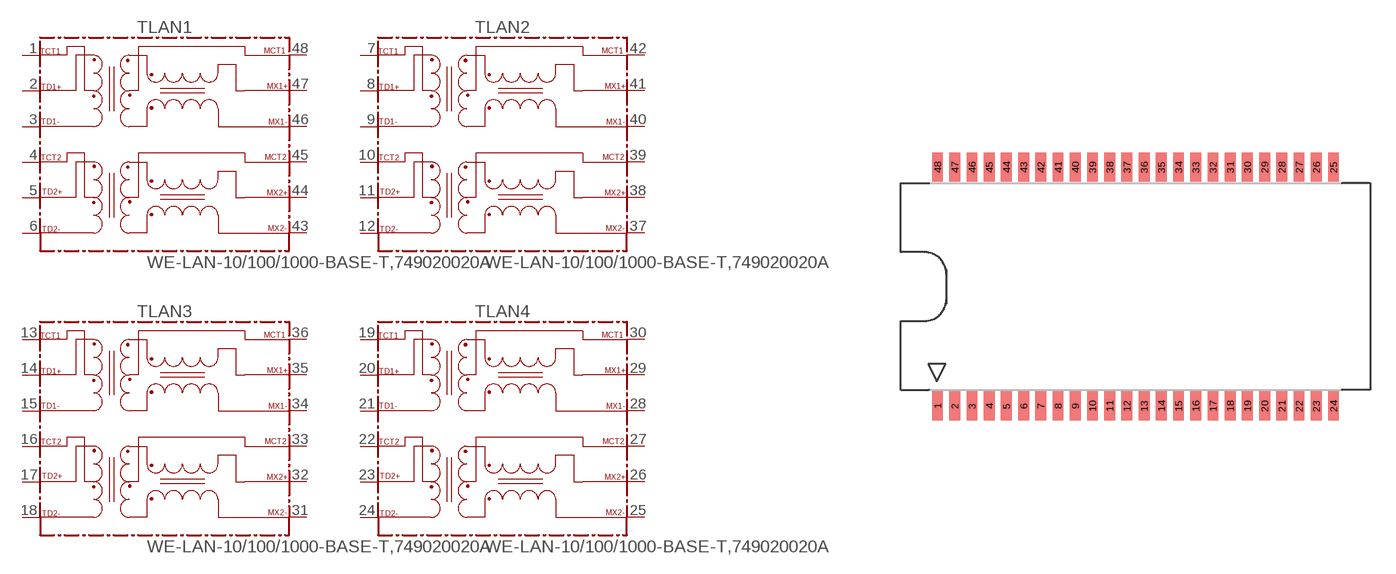
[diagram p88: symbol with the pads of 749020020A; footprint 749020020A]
Designator prefix T; gates LAN1=749020020A LAN2=749020020A LAN3=749020020A LAN4=749020020A

## WE-LAN-10/100/1000-BASE-T,749020020A (COMPANY-URL: http://www.we-online.de; CREATED-BY: Christin Zierenner; CREATED-DATE: June 2012; DATASHEET-URL: http://katalog.we-online.de/kataloge/eisos/media/pdf/749020020A.pdf; MANUFACTURER: Würth Elektronik eiSos GmbH)  [749020020A]
1  LAN1:TCT1
2  LAN1:TD1+
3  LAN1:TD1-
4  LAN1:TCT2
5  LAN1:TD2+
6  LAN1:TD2-
7  LAN2:TCT1
8  LAN2:TD1+
9  LAN2:TD1-
10  LAN2:TCT2
11  LAN2:TD2+
12  LAN2:TD2-
13  LAN3:TCT1
14  LAN3:TD1+
15  LAN3:TD1-
16  LAN3:TCT2
17  LAN3:TD2+
18  LAN3:TD2-
19  LAN4:TCT1
20  LAN4:TD1+
21  LAN4:TD1-
22  LAN4:TCT2
23  LAN4:TD2+
24  LAN4:TD2-
25  LAN4:MX2-
26  LAN4:MX2+
27  LAN4:MCT2
28  LAN4:MX1-
29  LAN4:MX1+
30  LAN4:MCT1
31  LAN3:MX2-
32  LAN3:MX2+
33  LAN3:MCT2
34  LAN3:MX1-
35  LAN3:MX1+
36  LAN3:MCT1
37  LAN2:MX2-
38  LAN2:MX2+
39  LAN2:MCT2
40  LAN2:MX1-
41  LAN2:MX1+
42  LAN2:MCT1
43  LAN1:MX2-
44  LAN1:MX2+
45  LAN1:MCT2
46  LAN1:MX1-
47  LAN1:MX1+
48  LAN1:MCT1

## Footprint 749020020A (pad centres in mm)
MAX Height = 7.70mm
smd 0.64 x 1.715: 1 -11.73,-7.082; 2 -10.71,-7.082; 3 -9.69,-7.082; 4 -8.67,-7.082; 5 -7.65,-7.082; 6 -6.63,-7.082; 7 -5.61,-7.082; 8 -4.59,-7.082; 9 -3.57,-7.082; 10 -2.55,-7.082; 11 -1.53,-7.082; 12 -0.51,-7.082; 13 0.51,-7.082; 14 1.53,-7.082; 15 2.55,-7.082; 16 3.57,-7.082; 17 4.59,-7.082; 18 5.61,-7.082; 19 6.63,-7.082; 20 7.65,-7.082; 21 8.67,-7.082; 22 9.69,-7.082; 23 10.71,-7.082; 24 11.73,-7.082; 25 11.73,7.082; 26 10.71,7.082; 27 9.69,7.082; 28 8.67,7.082; 29 7.65,7.082; 30 6.63,7.082; 31 5.61,7.082; 32 4.59,7.082; 33 3.57,7.082; 34 2.55,7.082; 35 1.53,7.082; 36 0.51,7.082; 37 -0.51,7.082; 38 -1.53,7.082; 39 -2.55,7.082; 40 -3.57,7.082; 41 -4.59,7.082; 42 -5.61,7.082; 43 -6.63,7.082; 44 -7.65,7.082; 45 -8.67,7.082; 46 -9.69,7.082; 47 -10.71,7.082; 48 -11.73,7.082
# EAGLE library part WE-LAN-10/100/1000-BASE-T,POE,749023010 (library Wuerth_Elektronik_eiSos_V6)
LAN-Transformer WE-LAN 10/10/1000 Base Tx - Compliant with IEEE 802.3 standards - SMD -- Ethernet -- Power over Ethernet -- 1 Gigabit Ethernet -- Compliant with most IC's for ethernet applications like Intel, AMD, Globespan and Realtek -- Hub, Router, Switch

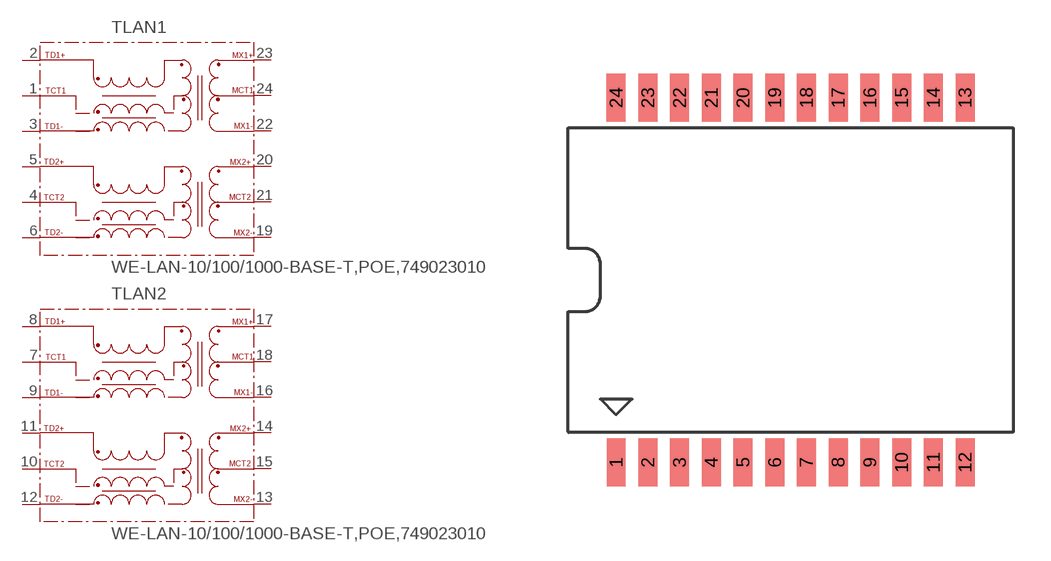
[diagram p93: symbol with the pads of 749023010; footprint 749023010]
Designator prefix T; gates LAN1=749023010 LAN2=749023010

## WE-LAN-10/100/1000-BASE-T,POE,749023010 (COMPANY-URL: http://www.we-online.de; CREATED-BY: Christin Zierenner; CREATED-DATE: June 2012; DATASHEET-URL: http://katalog.we-online.de/kataloge/eisos/media/pdf/749023010.pdf; MANUFACTURER: Würth Elektronik eiSos GmbH)  [749023010]
1  LAN1:TCT1
2  LAN1:TD1+
3  LAN1:TD1-
4  LAN1:TCT2
5  LAN1:TD2+
6  LAN1:TD2-
7  LAN2:TCT1
8  LAN2:TD1+
9  LAN2:TD1-
10  LAN2:TCT2
11  LAN2:TD2+
12  LAN2:TD2-
13  LAN2:MX2-
14  LAN2:MX2+
15  LAN2:MCT2
16  LAN2:MX1-
17  LAN2:MX1+
18  LAN2:MCT1
19  LAN1:MX2-
20  LAN1:MX2+
21  LAN1:MCT2
22  LAN1:MX1-
23  LAN1:MX1+
24  LAN1:MCT1

## Footprint 749023010 (pad centres in mm)
MAX Height = 6.5 mm
smd 0.76 x 1.905: 1 -6.985,-7.303; 2 -5.715,-7.303; 3 -4.445,-7.303; 4 -3.175,-7.303; 5 -1.905,-7.303; 6 -0.635,-7.303; 7 0.635,-7.303; 8 1.905,-7.303; 9 3.175,-7.303; 10 4.445,-7.303; 11 5.715,-7.303; 12 6.985,-7.303; 13 6.985,7.303; 14 5.715,7.303; 15 4.445,7.303; 16 3.175,7.303; 17 1.905,7.303; 18 0.635,7.303; 19 -0.635,7.303; 20 -1.905,7.303; 21 -3.175,7.303; 22 -4.445,7.303; 23 -5.715,7.303; 24 -6.985,7.303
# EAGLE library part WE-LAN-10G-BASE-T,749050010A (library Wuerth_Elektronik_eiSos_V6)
LAN-Transformer WE-LAN 10/10/1000 Base Tx - Compliant with IEEE 802.3 standards - SMD -- Ethernet -- Power over Ethernet -- 10 Gigabit Ethernet -- Compliant with most IC's for ethernet applications like Intel, AMD, Globespan and Realtek -- Hub, Router, Switch

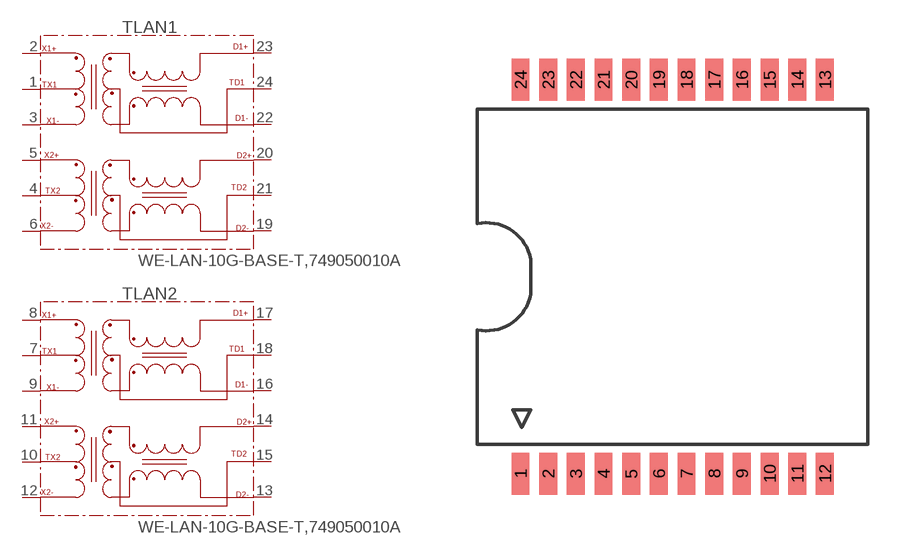
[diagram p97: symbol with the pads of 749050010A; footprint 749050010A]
Designator prefix T; gates LAN1=749050010A LAN2=749050010A

## WE-LAN-10G-BASE-T,749050010A (COMPANY-URL: http://www.we-online.de; CREATED-BY: Christin Zierenner; CREATED-DATE: June 2012; DATASHEET-URL: http://katalog.we-online.de/kataloge/eisos/media/pdf/749050010A.pdf; MANUFACTURER: Würth Elektronik eiSos GmbH)  [749050010A]
1  LAN1:TX1
2  LAN1:X1+
3  LAN1:X1-
4  LAN1:TX2
5  LAN1:X2+
6  LAN1:X2-
7  LAN2:TX1
8  LAN2:X1+
9  LAN2:X1-
10  LAN2:TX2
11  LAN2:X2+
12  LAN2:X2-
13  LAN2:D2-
14  LAN2:D2+
15  LAN2:TD2
16  LAN2:D1-
17  LAN2:D1+
18  LAN2:TD1
19  LAN1:D2-
20  LAN1:D2+
21  LAN1:TD2
22  LAN1:D1-
23  LAN1:D1+
24  LAN1:TD1

## Footprint 749050010A (pad centres in mm)
MAX Height = 6.32 mm
smd 0.64 x 1.5: 1 -5.445,-7.05; 2 -4.455,-7.05; 3 -3.465,-7.05; 4 -2.475,-7.05; 5 -1.485,-7.05; 6 -0.495,-7.05; 7 0.495,-7.05; 8 1.485,-7.05; 9 2.475,-7.05; 10 3.465,-7.05; 11 4.455,-7.05; 12 5.445,-7.05; 13 5.445,7.05; 14 4.455,7.05; 15 3.465,7.05; 16 2.475,7.05; 17 1.485,7.05; 18 0.495,7.05; 19 -0.495,7.05; 20 -1.485,7.05; 21 -2.475,7.05; 22 -3.465,7.05; 23 -4.455,7.05; 24 -5.445,7.05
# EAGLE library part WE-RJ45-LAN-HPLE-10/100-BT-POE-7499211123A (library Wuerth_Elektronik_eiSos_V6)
Order Code 7499211123A Design THT xBase-T 10/100 Base-T Ports 1x1 Application PoE HPLE Tab Position Down LED (Left-Right) YELLOW-GREEN EMI Fingers YES

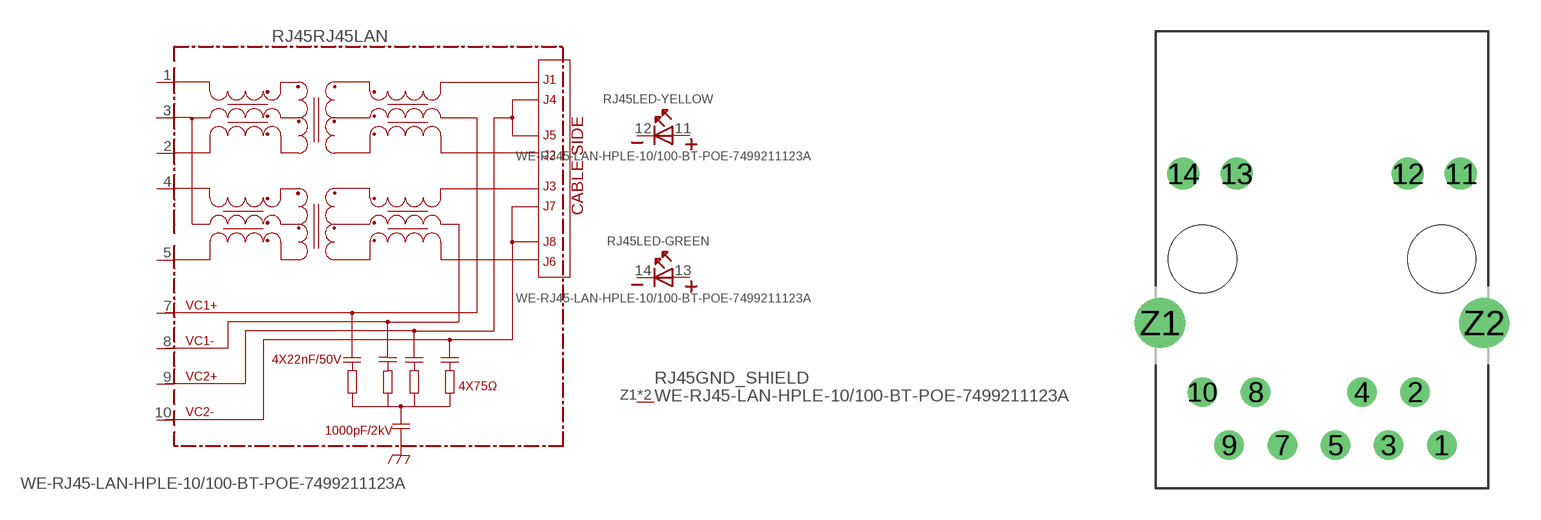
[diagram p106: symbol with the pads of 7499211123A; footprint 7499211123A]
Designator prefix RJ45; gates RJ45LAN=7499211123A LED-YELLOW=LED-2PIN LED-GREEN=LED-2PIN GND_SHIELD=GND_PIN

## WE-RJ45-LAN-HPLE-10/100-BT-POE-7499211123A (COMPANY-URL: http://www.we-online.de; CREATED-BY: Christin Zierenner; CREATED-DATE: AUG 2012; DATASHEET-URL: http://katalog.we-online.de/pbs/datasheet/7499211123A.pdf; MANUFACTURER: Würth Elektronik eiSos GmbH)  [7499211123A]
1  RJ45LAN:1
2  RJ45LAN:2
3  RJ45LAN:3
4  RJ45LAN:4
5  RJ45LAN:5
7  RJ45LAN:VC1+  pwr
8  RJ45LAN:VC1-  pwr
9  RJ45LAN:VC2+  pwr
10  RJ45LAN:VC2-  pwr
11  LED-YELLOW:A
12  LED-YELLOW:K
13  LED-GREEN:A
14  LED-GREEN:K
Z1  GND_SHIELD:P$1  pwr
Z2  GND_SHIELD:P$1  pwr

## Footprint 7499211123A (pad centres in mm)
MAX HEIGHT=13.95mm PORTS----1X1 LED --YES
drill 0.9: 1 5.715,-8.89; 2 4.445,-6.35; 3 3.175,-8.89; 4 1.905,-6.35; 5 0.635,-8.89; 7 -1.905,-8.89; 8 -3.175,-6.35; 9 -4.445,-8.89; 10 -5.715,-6.35
drill 1.02: 11 6.63,4.08; 12 4.09,4.08; 13 -4.09,4.08; 14 -6.63,4.08
drill 1.6: Z1 -7.745,-3.05; Z2 7.745,-3.05
hole 3.25 at 5.715,0
hole 3.25 at -5.715,0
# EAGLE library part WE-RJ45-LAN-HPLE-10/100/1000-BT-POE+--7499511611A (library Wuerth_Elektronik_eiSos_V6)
Order Code 7499511611A Design THT xBase-T 10/100/1000 Base-T Ports 1x1 Application PoE+ HPLE Tab Position Up LED (Left-Right) GREEN/ORANGE-YELLOW EMI Fingers YES

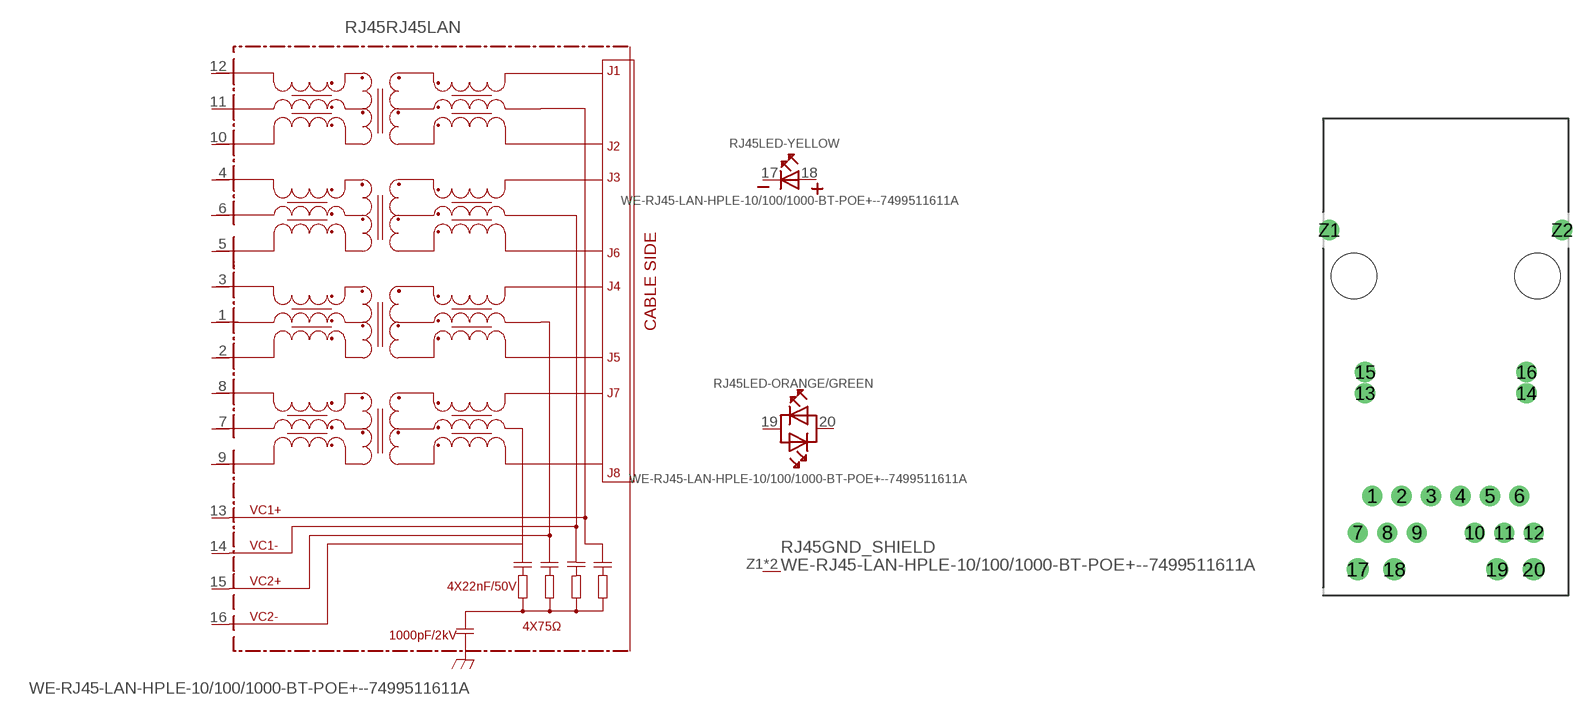
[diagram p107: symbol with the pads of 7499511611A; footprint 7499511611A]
Designator prefix RJ45; gates RJ45LAN=7499511611A LED-YELLOW=LED-2PIN LED-ORANGE/GREEN=LED-DUAL GND_SHIELD=GND_PIN

## WE-RJ45-LAN-HPLE-10/100/1000-BT-POE+--7499511611A (COMPANY-URL: http://www.we-online.de; CREATED-BY: Christin Zierenner; CREATED-DATE: AUG 2012; DATASHEET-URL: http://katalog.we-online.de/kataloge/eisos/media/pdf/7499511611A.pdf; MANUFACTURER: Würth Elektronik eiSos GmbH)  [7499511611A]
1  RJ45LAN:1
2  RJ45LAN:2
3  RJ45LAN:3
4  RJ45LAN:4
5  RJ45LAN:5
6  RJ45LAN:6
7  RJ45LAN:7
8  RJ45LAN:8
9  RJ45LAN:9
10  RJ45LAN:10
11  RJ45LAN:11
12  RJ45LAN:12
13  RJ45LAN:VC1+  pwr
14  RJ45LAN:VC1-  pwr
15  RJ45LAN:VC2+  pwr
16  RJ45LAN:VC2-  pwr
17  LED-YELLOW:K
18  LED-YELLOW:A
19  LED-ORANGE/GREEN:AK1
20  LED-ORANGE/GREEN:AK2
Z1  GND_SHIELD:P$1  pwr
Z2  GND_SHIELD:P$1  pwr

## Footprint 7499511611A (pad centres in mm)
MAX HEIGHT=13.87mm PORTS----1X1 LED --YES
drill 0.9: 1 -5.095,-15.24; 2 -3.055,-15.24; 3 -1.015,-15.24; 4 1.015,-15.24; 5 3.055,-15.24; 6 5.095,-15.24; 7 -6.09,-17.78; 8 -4.05,-17.78; 9 -2.01,-17.78; 10 2.01,-17.78; 11 4.05,-17.78; 12 6.09,-17.78; 13 -5.59,-8.12; 14 5.59,-8.12; 15 -5.59,-6.66; 16 5.59,-6.66; Z1 -8.065,3.18; Z2 8.065,3.18
drill 1.02: 17 -6.095,-20.32; 18 -3.555,-20.32; 19 3.555,-20.32; 20 6.095,-20.32
hole 3.15 at -6.35,0
hole 3.15 at 6.35,0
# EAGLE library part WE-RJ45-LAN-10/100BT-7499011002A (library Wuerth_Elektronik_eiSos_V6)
Order Code 7499011002A Design THT xBase-T 10/100 Base-T Ports 1x1 Application Standard Tab Position Down LED (Left-Right) NONE EMI Fingers Yes

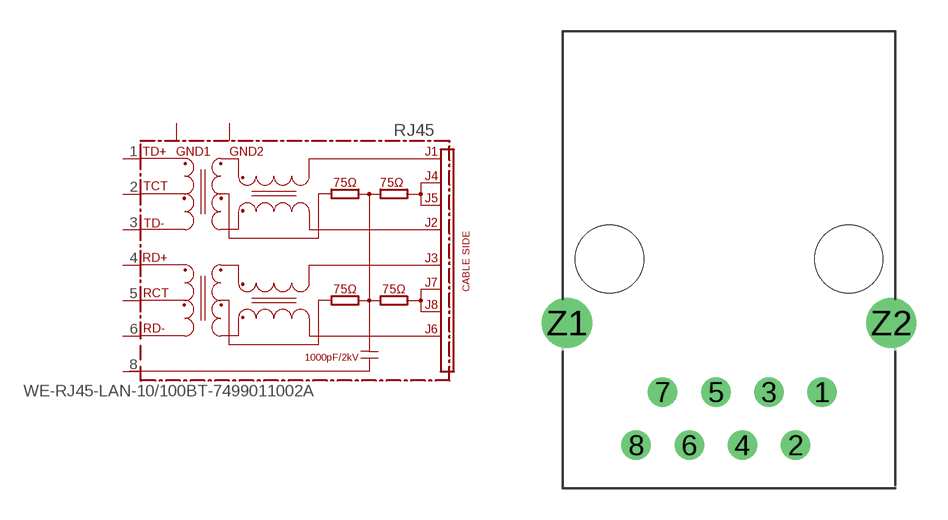
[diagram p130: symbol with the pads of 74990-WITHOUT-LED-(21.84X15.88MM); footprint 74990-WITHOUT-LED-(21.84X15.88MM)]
Designator prefix RJ45

## WE-RJ45-LAN-10/100BT-7499011002A (COMPANY-URL: http://www.we-online.de; CREATED-BY: Christin Zierenner; CREATED-DATE: AUG 2012; DATASHEET-URL: http://katalog.we-online.de/kataloge/eisos/media/pdf/7499011002A.pdf; MANUFACTURER: Würth Elektronik eiSos GmbH)  [74990-WITHOUT-LED-(21.84X15.88MM)]
1  TD+
2  TCT
3  TD-
4  RD+
5  RCT
6  RD-
8  SH  pwr

## Footprint 74990-WITHOUT-LED-(21.84X15.88MM) (pad centres in mm)
MAX HEIGHT=13.95mm PORTS----1X1 LED ----NO
drill 0.9: 1 4.445,-6.35; 2 3.175,-8.89; 3 1.905,-6.35; 4 0.635,-8.89; 5 -0.635,-6.35; 6 -1.905,-8.89; 7 -3.175,-6.35; 8 -4.445,-8.89
drill 1.6: Z1 -7.745,-3.05; Z2 7.745,-3.05
hole 3.25 at 5.715,0
hole 3.25 at -5.715,0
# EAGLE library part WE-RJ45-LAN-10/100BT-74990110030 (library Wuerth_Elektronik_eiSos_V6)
Order Code 74990110030 Design THT xBase-T 10/100 Base-T Ports 1x1 Application Standard Tab Position UP LED (Left-Right) NONE EMI Fingers Yes

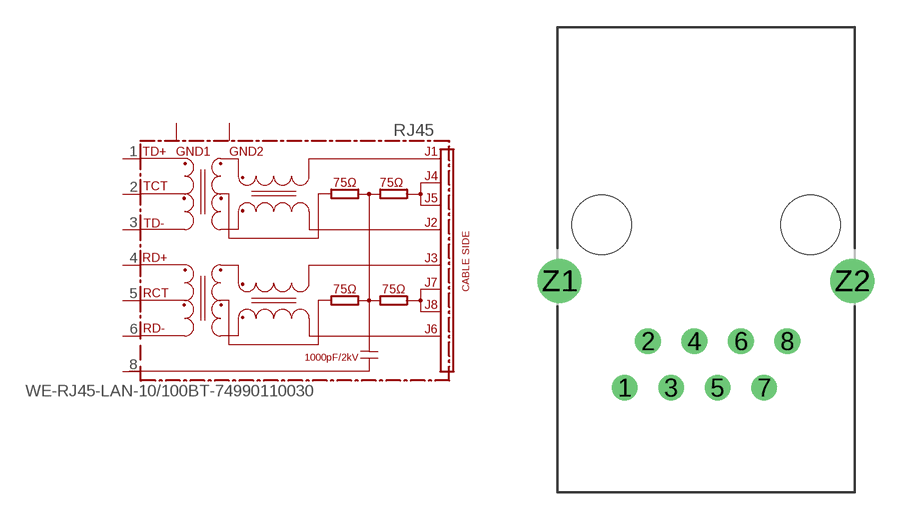
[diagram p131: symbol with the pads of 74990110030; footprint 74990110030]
Designator prefix RJ45

## WE-RJ45-LAN-10/100BT-74990110030 (COMPANY-URL: http://www.we-online.de; CREATED-BY: Christin Zierenner; CREATED-DATE: AUG 2012; DATASHEET-URL: http://katalog.we-online.de/kataloge/eisos/media/pdf/74990110030.pdf; MANUFACTURER: Würth Elektronik eiSos GmbH)  [74990110030]
1  TD+
2  TCT
3  TD-
4  RD+
5  RCT
6  RD-
8  SH  pwr

## Footprint 74990110030 (pad centres in mm)
MAX HEIGHT=13.50mm PORTS----1X1 LED --NO
drill 0.9: 1 -4.445,-8.89; 2 -3.175,-6.35; 3 -1.905,-8.89; 4 -0.635,-6.35; 5 0.635,-8.89; 6 1.905,-6.35; 7 3.175,-8.89; 8 4.445,-6.35
drill 1.6: Z1 -8,-3.05; Z2 8,-3.05
hole 3.25 at 5.715,0
hole 3.25 at -5.715,0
